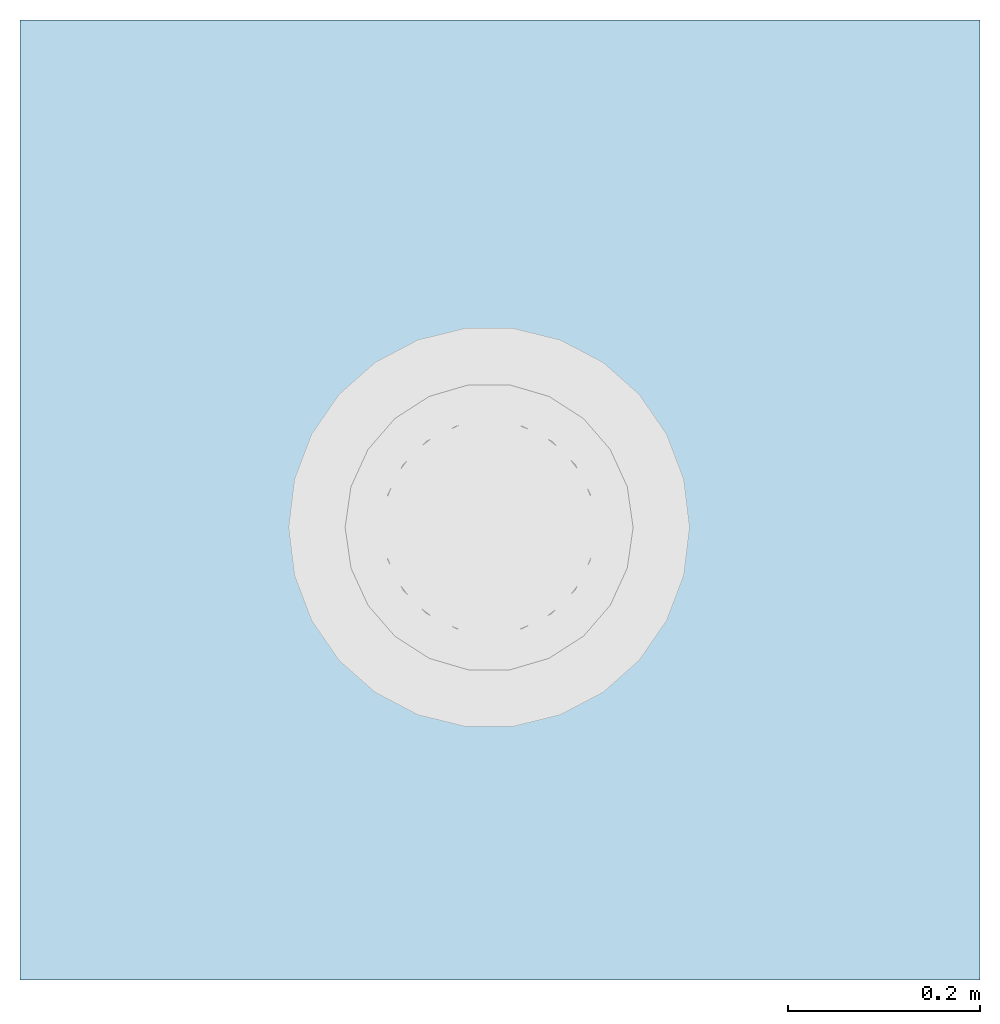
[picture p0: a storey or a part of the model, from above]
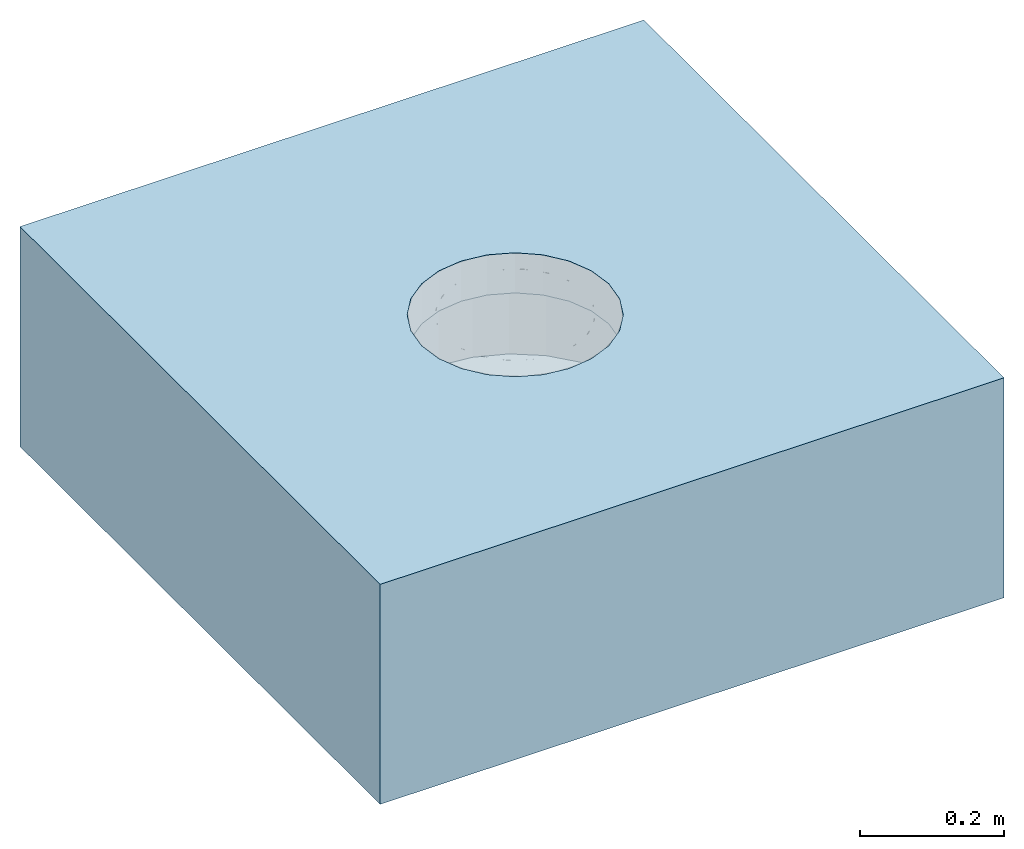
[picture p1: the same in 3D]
Properties of the parts of a building model (IFC2X3)

# File
Description: ViewDefinition [CoordinationView]
File name: Project Number
Time: 2014-10-21T15:00:18
Written by: The EXPRESS Data Manager Version 5.01.0100.02.64mod : 6 Jun 2012
Made in: 20130308_1515(x64) - Exporter 2014.0.2013.0308 - Default UI
Comment: STEP Physical File produced by: The EXPRESS Data Manager Version 5.01.0100.02.64mod : 6 Jun 2012 * Module: EDMstepFileFactory/EDMstandAlone * Creation date: Tue Oct 21 15:00:18 2014 * Host: IN-BLR-PC-0012 * Database: C:\Users\pponnur\AppData\Local\Temp\{7B0EEBDC-D62A-44E5-9330-8CD6FCDA56F0}\ifc * Database version: 5507 * Database creation date: Tue Oct 21 15:00:16 2014 * Schema: IFC2X3 * Model: DataRepository.ifc * Model creation date: Tue Oct 21 15:00:17 2014 * Header model: DataRepository.ifc_HeaderModel * Header model creation date: Tue Oct 21 15:00:17 2014 * EDMuser: sdai-user * EDMgroup: sdai-group * License ID and type: 5605 : Permanent license. Expiry date: * EDMstepFileFactory options: 020000

# IfcProject, Project Number
LongName: Project Name; Phase: Project Status

# IfcSite, Default
RefLatitude: 42, 21, 30, 344238; RefLongitude: -71, -3, -35, -194702; RefElevation: 0 mm

# IfcBuilding
Pset_BuildingCommon - NumberOfStoreys: 1
Other - Project Address: Enter address here; Project Issue Date: Issue Date; Project Name: Project Name; Client Name: Owner; Project Status: Project Status; Project Number: Project Number

# IfcBuildingStorey, Level 1
LongName: Level 1; Elevation: 0 mm
Constraints - Elevation Base: Project Base Point; Elevation: 0 mm
Graphics - Symbol at End 2 Default: yes; Symbol at End 1 Default: no; Line Pattern: Grid Line 1/2"; Line Weight: 1; Color: 0; Symbol: Level Head - Circle: Level Head - Circle
Identity Data - Structural: no; Building Story: yes; Name: Level 1
Dimensions - Computation Height: 0 mm

# IfcFlowTerminal: 408087 Body / 408242 Top, ACO BD Gully 218 Telescopic - Vinyl Top - Horizontal Outlet with Adhesive Flange - 222 mm:408087 Body / 408242 Top:198822
In: Level 1
Material: Stainless Steel AISI 304, Rubber, Nitrile
Materials and Finishes - Material: Stainless Steel AISI 304
Identity Data - Mark: 5; Water Marked With: BIM Manager Premium Suite; Water Mark 2: This file is water marked and users are prohibited to reproduce, adapt, distribute this information; Manufacturer: ACO Building Drainage; Address: ACO Business Centre, Caxton Road, Bedford, MK41 0LF; Website: www.acobd.com; Watermarked By: www.acobd.com; Fax: +44 (0)1462 851490; E-mail Technical: abdtechnical@aco.co.uk; E-mail Sales: abdcommercial@aco.co.uk; Water Mark 1: This file is the property of ACO Technologies PLC; Telephone: +44 (0)1462 816666
Mechanical - System Classification: Sanitary
Phasing - Phase Created: New Construction
Constraints - Level: Level: Level 1
Other - Floor Void End: -215 mm; Raising Piece Detail: no; Floor to Gully Height: 68 mm; Raising Piece Position Height: 500 mm; 408226 - Raising piece with adhesive bonding flange: no; Gully Void Start: 0 mm; Grating 300 x 300mm: yes; Gully Top: yes; 408087 - Telescopic Horizontal Gully & 408225 - Friction Ring: yes
Model Properties - Raising Piece Product Code 408226: NA; Grating Product Code 97148: Load Class M125 (EN 1253) - Ladder Grating - Plain - Stainless steel 1.4301 (EN 10088) - 222mm Ø; Product Code 408220: Foul Air Trap - Stainless Steel 304; Grating Product Code 97156: Load Class M125 (EN 1253) - Slot Grating - Plain - Stainless steel 1.4301 (EN 10088) - 222mm Ø; Product Code 408225: Friction Ring Installation Set - Nitrile; Grating Product Code 97153: Load Class L15 (EN 1253) - Perforated Grating - Plain - Stainless steel 1.4301 (EN 10088) - 222mm Ø; Product Code 408221: Foul Air Trap Support Ring - Nitrile; Product Code 408223: Silt Basket - Stainless Steel 304
Construction - 97148 - 222mm Ø - Ladder Grating - Plain - Stainless steel 304: no; 408220 - Foul Air Trap & 408221 - Foul Air Trap Support Ring: yes; 97153 - 222mm Ø - Perforated Grating - Plain - Stainless steel 304: no; 97156 - 222mm Ø - Slot Grating - Plain - Stainless steel 304: no; 408223 - Silt Basket: yes
Dimensions - FFL To Gully Top Height: 68 mm; Seepage Water Removal Pipe End: -8.5 mm
Pset_ManufacturerTypeInformation - Manufacturer: ACO Building Drainage
General - Gully Recyclable: Fully Recyclable; Flow Rate (l/s): 4.4 - 5.5 l/s; Gully Material: Stainless Steel Grade 304 (EN 1253); Foul Air Trap Seal Recycled Material Content: 0%; Gully Recycled Material Content: 20 - 30 %; Foul Air Trap Seal Colour: Black; Gully Product Code: 408087; Gully Top Product Code: 408242; Gully Top Size (mm): 242mm Diameter; Product Standard: EN 1253; Gully Product Description: ACO Gully 218 Telescopic Flange Type DN110 Horizontal with Foul Air Trap; Gully Top Product Description: ACO Gully 218 Telescopic Top for Vinyl Floor; Product Range: ACO Gully 218; Installation guidelines: http://issuu.com/acobuildingdrainage/docs/120820112708-138bdc871b784edfa2b6b8197acfd881?e=0; Product Type: Point Drainage; Gully Colour: passivated stainless steel surface ( matt grey); NBS Specification: R11 ABOVE GROUND FOUL DRAINAGE SYSTEMS : Clause 315; Outlet Diameter (mm): 110; Maintenance guidelines: http://issuu.com/acobuildingdrainage/docs/120820112708-138bdc871b784edfa2b6b8197acfd881?e=0; Foul Air Trap Seal Material: NBR; Load Class: A15 - C250 (EN 1253); Gully Flange Type: Adhesive; Price: POA - contact ACO; Gully top Grate size (mm): 222; Foul Air Trap Seal Recyclable: Fully Recyclable

# IfcOpeningElement: Recess
In: Level 1
Dimensions - Area: 10.7639 ft2; Perimeter: 4000 mm; Volume: 12.2584 ft3; Thickness: 372.8 mm
Constraints - Height Offset From Level: 0 mm; Level: Level: Level 1; Related to Mass: no; Room Bounding: yes
Structural - Enable Analytical Model: no; Structural: no
Phasing - Phase Created: New Construction
Identity Data - Assembly Description: Floor Construction; Assembly Code: B1010
Graphics - Coarse Scale Fill Color: 0
Analytical Properties - Thermal Resistance (R): 0.641509; Absorptance: 0.7; Thermal mass: 53301.1; Heat Transfer Coefficient (U): 1.55882; Roughness: 3
Construction - Function: Interior; Default Thickness: 372.8 mm

# IfcSlab: Floor:Generic - 12", Floor:Generic - 12":184145
In: Level 1
PredefinedType: FLOOR; Material: Plywood, Sheathing 68 mm, Default Floor 304.8 mm
Dimensions - Area: 10.7639 ft2; Perimeter: 4000 mm; Volume: 12.2584 ft3; Thickness: 372.8 mm
Constraints - Height Offset From Level: 0 mm; Level: Level: Level 1; Related to Mass: no; Room Bounding: yes
Structural - Enable Analytical Model: no; Structural: no
Phasing - Phase Created: New Construction
Pset_SlabCommon - Reference: Generic - 12"; IsExternal: no; LoadBearing: yes; ThermalTransmittance: 1.55882 kg/K/s3
Identity Data - Assembly Description: Floor Construction; Assembly Code: B1010
Graphics - Coarse Scale Fill Color: 0
Analytical Properties - Thermal Resistance (R): 0.641509; Absorptance: 0.7; Thermal mass: 53301.1; Heat Transfer Coefficient (U): 1.55882; Roughness: 3
Construction - Function: Interior; Default Thickness: 372.8 mm
